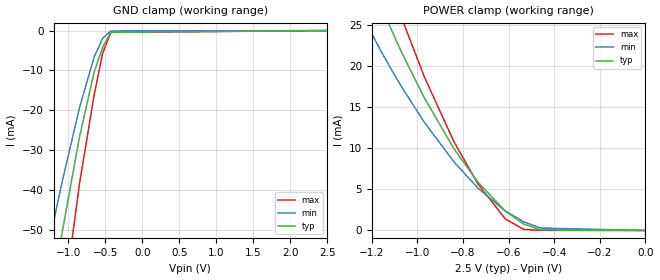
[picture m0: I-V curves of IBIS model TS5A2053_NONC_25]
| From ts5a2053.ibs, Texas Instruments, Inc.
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[Model]   TS5A2053_NONC_25
Model_type  Terminator
| variable   typ   min   max
C_comp   7.10pF   6.35pF   7.79pF
| C_tri-state   7.10pF   6.35pF   7.79pF
[Temperature Range]   40   100   -40
| Ambient temperature   25   85   -40
[Voltage range]   2.5   2.3   2.7
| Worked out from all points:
|   GND clamp passes 1 mA (typ) near -0.45 V on its own axis
|   POWER clamp passes 1 mA (typ) near -0.55 V on its own axis
[GND Clamp]
| TS5A2053_NONC_25
|   Voltage   I(typ)   I(min)   I(max)
-5.5V     -656.6mA   -514.9mA   -884.2mA
-1.535V   -103.3mA   -79.17mA   -142mA
-1.48V    -96.63mA   -73.9mA    -132.9mA
-1.325V   -78.11mA   -59.37mA   -108mA
-1.275V   -72.28mA   -54.81mA   -100.2mA
-1.13V    -55.84mA   -41.96mA   -78.01mA
-1.085V   -50.9mA    -38.12mA   -71.33mA
-850mV    -26.79mA   -19.45mA   -38.62mA
-650mV    -10.4mA    -6.588mA   -16.1mA
-535mV    -4.195mA   -1.922mA   -5.672mA
-425mV    -416.9uA   -96.64uA   -455.7uA
2.5V      412.2pA    377.8nA    3.501nA
[POWER Clamp]
| TS5A2053_NONC_25
|   Voltage   I(typ)   I(min)   I(max)
-5.5V     619.8mA    493.6mA    807.7mA
-1.26V    34.03mA    27.02mA    41.99mA
-1.16V    27.26mA    21.78mA    33.13mA
-1.095V   23.18mA    18.63mA    27.82mA
-1.065V   21.39mA    17.24mA    25.5mA
-970mV    16.12mA    13.15mA    18.68mA
-840mV    9.933mA    8.337mA    10.78mA
-735mV    5.874mA    5.157mA    5.669mA
-615mV    2.368mA    2.37mA     1.415mA
-535mV    798.2uA    1.064mA    142uA
-460mV    73.09uA    298.5uA    18.02uA
-95.1fV   412.2pA    2.73nA     9.341nA
